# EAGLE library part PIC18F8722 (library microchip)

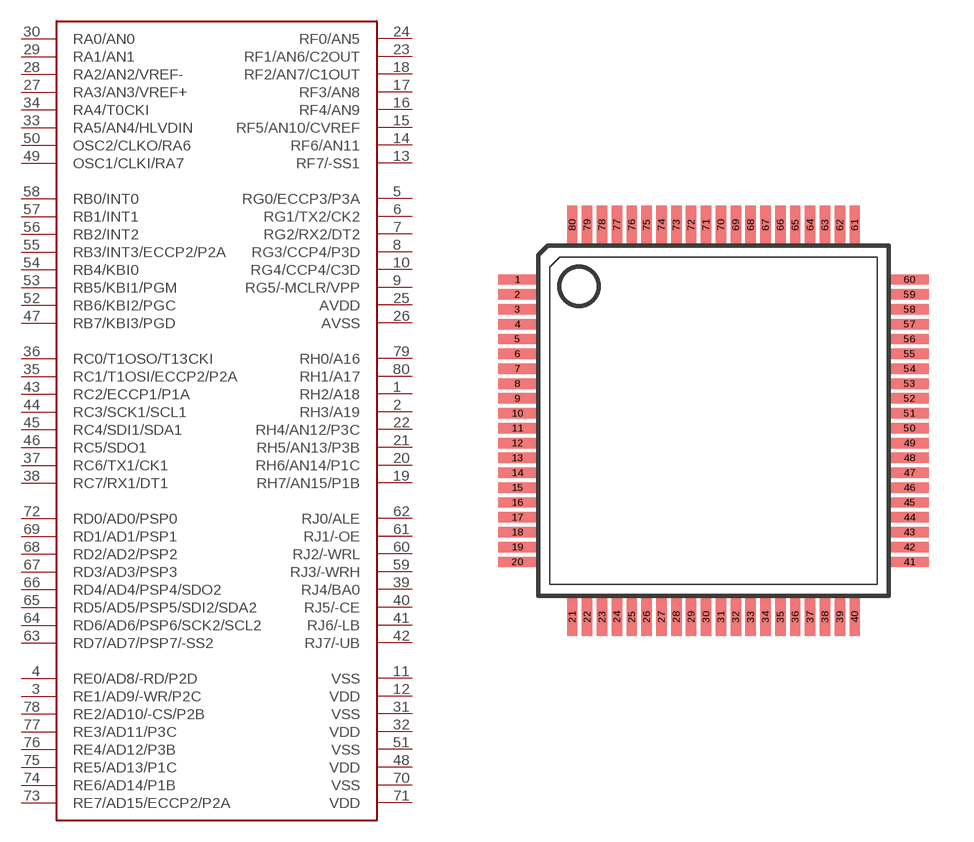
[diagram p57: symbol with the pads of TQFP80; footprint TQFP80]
Designator prefix IC

## PIC18F8722  [TQFP80]
1  RH2/A18
2  RH3/A19
3  RE1/AD9/-WR/P2C
4  RE0/AD8/-RD/P2D
5  RG0/ECCP3/P3A
6  RG1/TX2/CK2
7  RG2/RX2/DT2
8  RG3/CCP4/P3D
9  RG5/-MCLR/VPP
10  RG4/CCP4/C3D
11  VSS  pwr
12  VDD  pwr
13  RF7/-SS1
14  RF6/AN11
15  RF5/AN10/CVREF
16  RF4/AN9
17  RF3/AN8
18  RF2/AN7/C1OUT
19  RH7/AN15/P1B
20  RH6/AN14/P1C
21  RH5/AN13/P3B
22  RH4/AN12/P3C
23  RF1/AN6/C2OUT
24  RF0/AN5
25  AVDD  pwr
26  AVSS  pwr
27  RA3/AN3/VREF+
28  RA2/AN2/VREF-
29  RA1/AN1
30  RA0/AN0
31  VSS  pwr
32  VDD  pwr
33  RA5/AN4/HLVDIN
34  RA4/T0CKI
35  RC1/T1OSI/ECCP2/P2A
36  RC0/T1OSO/T13CKI
37  RC6/TX1/CK1
38  RC7/RX1/DT1
39  RJ4/BA0
40  RJ5/-CE
41  RJ6/-LB
42  RJ7/-UB
43  RC2/ECCP1/P1A
44  RC3/SCK1/SCL1
45  RC4/SDI1/SDA1
46  RC5/SDO1
47  RB7/KBI3/PGD
48  VDD  pwr
49  OSC1/CLKI/RA7
50  OSC2/CLKO/RA6
51  VSS  pwr
52  RB6/KBI2/PGC
53  RB5/KBI1/PGM
54  RB4/KBI0
55  RB3/INT3/ECCP2/P2A
56  RB2/INT2
57  RB1/INT1
58  RB0/INT0
59  RJ3/-WRH
60  RJ2/-WRL
61  RJ1/-OE
62  RJ0/ALE
63  RD7/AD7/PSP7/-SS2
64  RD6/AD6/PSP6/SCK2/SCL2
65  RD5/AD5/PSP5/SDI2/SDA2
66  RD4/AD4/PSP4/SDO2
67  RD3/AD3/PSP3
68  RD2/AD2/PSP2
69  RD1/AD1/PSP1
70  VSS  pwr
71  VDD  pwr
72  RD0/AD0/PSP0
73  RE7/AD15/ECCP2/P2A
74  RE6/AD14/P1B
75  RE5/AD13/P1C
76  RE4/AD12/P3B
77  RE3/AD11/P3C
78  RE2/AD10/-CS/P2B
79  RH0/A16
80  RH1/A17

## Footprint TQFP80 (pad centres in mm)
Thin Quad Flat Pack
smd 1.3 x 0.35: 1 -6.595,4.75; 2 -6.595,4.25; 3 -6.595,3.75; 4 -6.595,3.25; 5 -6.595,2.75; 6 -6.595,2.25; 7 -6.595,1.75; 8 -6.595,1.25; 9 -6.595,0.75; 10 -6.595,0.25; 11 -6.595,-0.25; 12 -6.595,-0.75; 13 -6.595,-1.25; 14 -6.595,-1.75; 15 -6.595,-2.25; 16 -6.595,-2.75; 17 -6.595,-3.25; 18 -6.595,-3.75; 19 -6.595,-4.25; 20 -6.595,-4.75; 41 6.595,-4.75; 42 6.595,-4.25; 43 6.595,-3.75; 44 6.595,-3.25; 45 6.595,-2.75; 46 6.595,-2.25; 47 6.595,-1.75; 48 6.595,-1.25; 49 6.595,-0.75; 50 6.595,-0.25; 51 6.595,0.25; 52 6.595,0.75; 53 6.595,1.25; 54 6.595,1.75; 55 6.595,2.25; 56 6.595,2.75; 57 6.595,3.25; 58 6.595,3.75; 59 6.595,4.25; 60 6.595,4.75
smd 0.35 x 1.3: 21 -4.75,-6.595; 22 -4.25,-6.595; 23 -3.75,-6.595; 24 -3.25,-6.595; 25 -2.75,-6.595; 26 -2.25,-6.595; 27 -1.75,-6.595; 28 -1.25,-6.595; 29 -0.75,-6.595; 30 -0.25,-6.595; 31 0.25,-6.595; 32 0.75,-6.595; 33 1.25,-6.595; 34 1.75,-6.595; 35 2.25,-6.595; 36 2.75,-6.595; 37 3.25,-6.595; 38 3.75,-6.595; 39 4.25,-6.595; 40 4.75,-6.595; 61 4.75,6.595; 62 4.25,6.595; 63 3.75,6.595; 64 3.25,6.595; 65 2.75,6.595; 66 2.25,6.595; 67 1.75,6.595; 68 1.25,6.595; 69 0.75,6.595; 70 0.25,6.595; 71 -0.25,6.595; 72 -0.75,6.595; 73 -1.25,6.595; 74 -1.75,6.595; 75 -2.25,6.595; 76 -2.75,6.595; 77 -3.25,6.595; 78 -3.75,6.595; 79 -4.25,6.595; 80 -4.75,6.595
